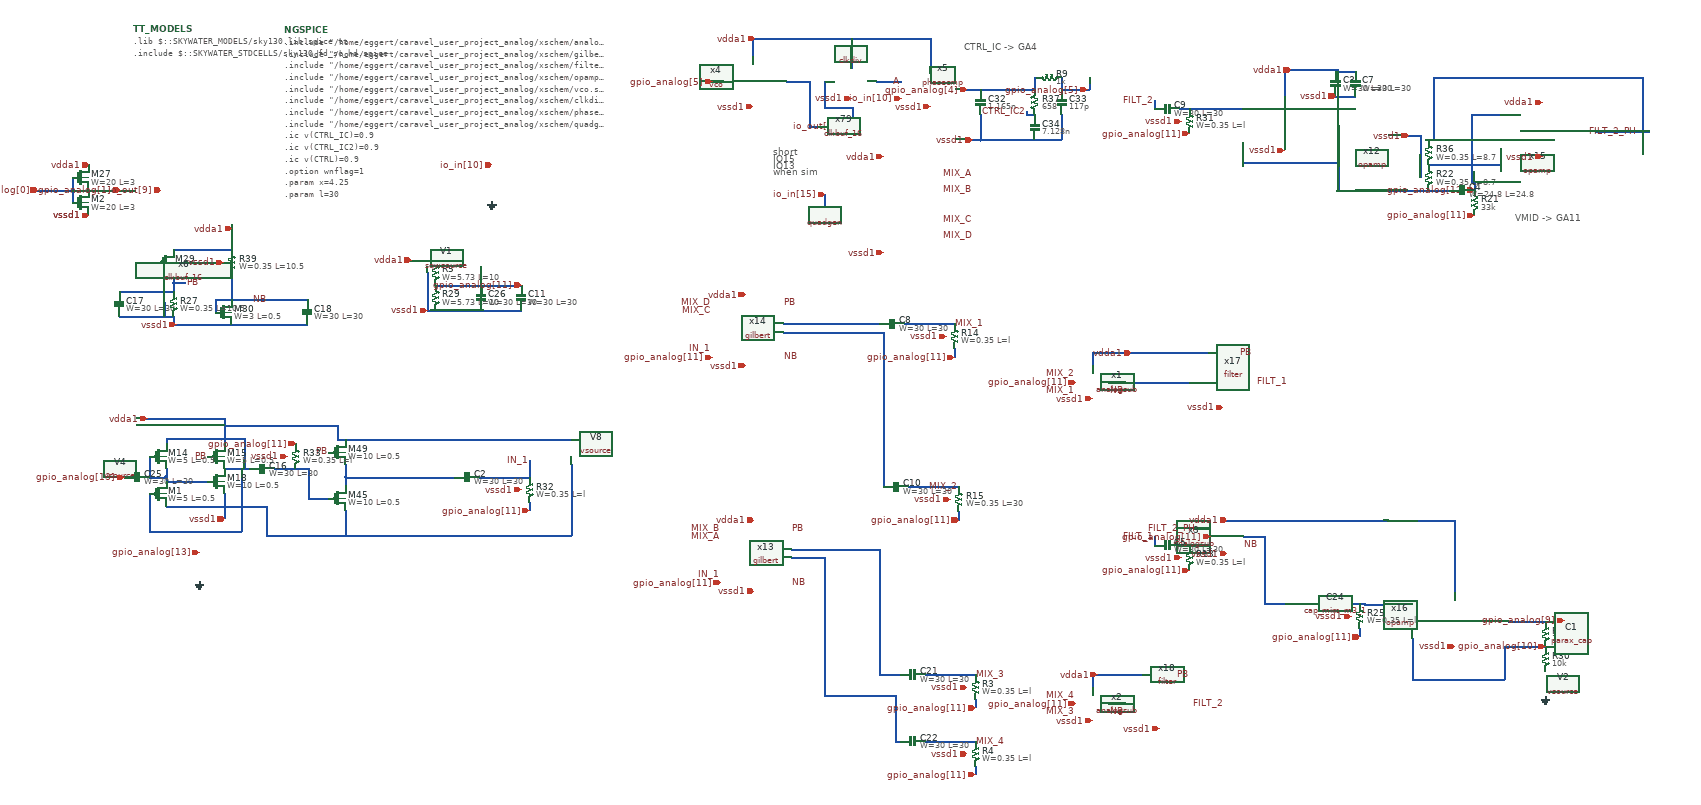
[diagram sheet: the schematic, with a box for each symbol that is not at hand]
v {xschem version=3.1.0 file_version=1.2 }
G {}
K {}
V {}
S {}
E {}
T {short 
IO15
IO13
when sim} 47.5 -2042.5 0 0 0.4 0.4 {}
T {VMID -> GA11} 1822.5 -1885 0 0 0.4 0.4 {}
T {CTRL_IC -> GA4} 505 -2295 0 0 0.4 0.4 {}
N -657.5 -1252.5 -537.5 -1252.5 {
lab=IN_1}
N -997.5 -1342.5 -437.5 -1342.5 {
lab=vdda1}
N 1395 -1940 1565 -1940 {
lab=#net1}
N 960 -2155 960 -2135 {
lab=FILT_2}
N 2135 -2080 2145 -2080 {
lab=FILT_2_PH}
N 1555 -1940 1665 -1940 {
lab=#net1}
N 1725 -1960 1725 -1940 {
lab=gpio_analog[12]}
N -437.5 -1282.5 -437.5 -1112.5 {
lab=vssd1}
N -1167.5 -1112.5 -977.5 -1112.5 {
lab=vssd1}
N -1067.5 -1202.5 -1017.5 -1202.5 {
lab=#net2}
N -977.5 -1252.5 -977.5 -1232.5 {
lab=#net3}
N -977.5 -1172.5 -977.5 -1112.5 {
lab=vssd1}
N -977.5 -1112.5 -437.5 -1112.5 {
lab=vssd1}
N -977.5 -1252.5 -717.5 -1252.5 {
lab=#net3}
N -762.5 -1712.5 -642.5 -1712.5 {
lab=gpio_analog[11]}
N 882.5 -1480 1042.5 -1480 {
lab=#net4}
N -1290 -1677.5 -1250 -1677.5 {
lab=NB}
N -1290 -1677.5 -1290 -1647.5 {
lab=NB}
N -1250 -1737.5 -1250 -1677.5 {
lab=NB}
N -1250 -1857.5 -1250 -1797.5 {
lab=vdda1}
N -1250 -1677.5 -1070 -1677.5 {
lab=NB}
N -1430 -1767.5 -1430 -1737.5 {
lab=PB}
N -1430 -1737.5 -1390 -1737.5 {
lab=PB}
N -1390 -1797.5 -1250 -1797.5 {
lab=vdda1}
N -1390 -1717.5 -1390 -1697.5 {
lab=PB}
N -1390 -1637.5 -1390 -1617.5 {
lab=vssd1}
N -1390 -1617.5 -1250 -1617.5 {
lab=vssd1}
N -1390 -1717.5 -1360 -1717.5 {
lab=PB}
N -1407.5 -1392.5 -1267.5 -1392.5 {
lab=vdda1}
N -1457.5 -1392.5 -1407.5 -1392.5 {
lab=vdda1}
N -1267.5 -1392.5 -1267.5 -1332.5 {
lab=vdda1}
N -1067.5 -1272.5 -1067.5 -1202.5 {
lab=#net2}
N -1267.5 -1272.5 -1207.5 -1272.5 {
lab=#net5}
N -1520 -1697.5 -1390 -1697.5 {
lab=PB}
N -1520 -1637.5 -1390 -1637.5 {
lab=vssd1}
N -1147.5 -1272.5 -1067.5 -1272.5 {
lab=#net2}
N -537.5 -1292.5 -537.5 -1252.5 {
lab=IN_1}
N -537.5 -1192.5 -537.5 -1172.5 {
lab=gpio_analog[11]}
N 370 -1230 490 -1230 {
lab=MIX_2}
N 490 -1170 490 -1150 {
lab=gpio_analog[11]}
N 310 -1310 310 -1230 {
lab=#net6}
N 410 -780 530 -780 {
lab=MIX_3}
N 530 -720 530 -700 {
lab=gpio_analog[11]}
N 410 -620 530 -620 {
lab=MIX_4}
N 530 -560 530 -540 {
lab=gpio_analog[11]}
N 340 -730 340 -620 {
lab=#net7}
N 340 -620 350 -620 {
lab=#net7}
N -1267.5 -1212.5 -1267.5 -1152.5 {
lab=vssd1}
N -1407.5 -1252.5 -1407.5 -1242.5 {
lab=#net8}
N -1407.5 -1242.5 -1307.5 -1242.5 {
lab=#net8}
N -1447.5 -1252.5 -1407.5 -1252.5 {
lab=#net8}
N -782.5 -1772.5 -762.5 -1772.5 {
lab=vdda1}
N 1595 -2070 1595 -1970 {
lab=vssd1}
N 1565 -2070 1595 -2070 {
lab=vssd1}
N 2015 -2080 2135 -2080 {
lab=FILT_2_PH}
N -977.5 -1282.5 -977.5 -1252.5 {
lab=#net3}
N -1390 -1737.5 -1390 -1717.5 {
lab=PB}
N -1407.5 -1272.5 -1407.5 -1252.5 {
lab=#net8}
N -822.5 -1772.5 -782.5 -1772.5 {
lab=vdda1}
N -107.5 -2200 -72.5 -2200 {
lab=gpio_analog[5]}
N -2.5 -2290 -2.5 -2260 {
lab=vdda1}
N 737.5 -2120 737.5 -2060 {
lab=vssd1}
N 542.5 -2060 737.5 -2060 {
lab=vssd1}
N 542.5 -2120 542.5 -2060 {
lab=vssd1}
N 502.5 -2180 587.5 -2180 {
lab=gpio_analog[4]}
N 647.5 -2180 672.5 -2180 {
lab=gpio_analog[4]}
N 517.5 -2060 542.5 -2060 {
lab=vssd1}
N 737.5 -2180 802.5 -2180 {
lab=gpio_analog[5]}
N 802.5 -2210 802.5 -2180 {
lab=gpio_analog[5]}
N 672.5 -2210 677.5 -2210 {
lab=gpio_analog[4]}
N 672.5 -2210 672.5 -2180 {
lab=gpio_analog[4]}
N 737.5 -2210 737.5 -2180 {
lab=gpio_analog[5]}
N 587.5 -2180 647.5 -2180 {
lab=gpio_analog[4]}
N 652.5 -2127.5 652.5 -2120 {
lab=CTRL_IC2}
N 652.5 -2120 672.5 -2120 {
lab=CTRL_IC2}
N 850 -1480 890 -1480 {
lab=#net4}
N 850 -710 890 -710 {
lab=#net9}
N 360 -1620 480 -1620 {
lab=MIX_1}
N 480 -1560 480 -1540 {
lab=gpio_analog[11]}
N 70 -1620 300 -1620 {
lab=#net10}
N 370 -1230 490 -1230 {
lab=MIX_2}
N 490 -1170 490 -1150 {
lab=gpio_analog[11]}
N 70 -1600 310 -1600 {
lab=#net6}
N 310 -1600 310 -1310 {
lab=#net6}
N 90 -1080 300 -1080 {
lab=#net11}
N 300 -1080 300 -780 {
lab=#net11}
N 90 -1060 170 -1060 {
lab=#net7}
N 170 -1060 170 -730 {
lab=#net7}
N 300 -780 350 -780 {
lab=#net11}
N 170 -730 340 -730 {
lab=#net7}
N 1717.5 -1960 1727.5 -1960 {
lab=gpio_analog[12]}
N 1807.5 -907.5 1897.5 -907.5 {
lab=gpio_analog[9]}
N 1797.5 -847.5 1897.5 -847.5 {
lab=gpio_analog[10]}
N 1797.5 -847.5 1797.5 -767.5 {
lab=gpio_analog[10]}
N 1577.5 -767.5 1797.5 -767.5 {
lab=gpio_analog[10]}
N 1577.5 -867.5 1577.5 -767.5 {
lab=gpio_analog[10]}
N 1450 -890 1450 -870 {
lab=gpio_analog[11]}
N 1052.5 -1130 1092.5 -1130 {
lab=FILT_2_PH}
N 1172.5 -1110 1222.5 -1110 {
lab=#net12}
N 1222.5 -1110 1222.5 -950 {
lab=#net12}
N 960 -1110 960 -1090 {
lab=FILT_1}
N 1022.5 -1090 1092.5 -1090 {
lab=#net13}
N 1012.5 -1090 1022.5 -1090 {
lab=#net13}
N 1222.5 -950 1272.5 -950 {
lab=#net12}
N 1322.5 -950 1332.5 -950 {
lab=#net14}
N 1322.5 -950 1462.5 -950 {
lab=#net14}
N 1787.5 -2040 1787.5 -2000 {
lab=#net15}
N 1617.5 -2000 1787.5 -2000 {
lab=#net15}
N 1717.5 -2120 1717.5 -1960 {
lab=gpio_analog[12]}
N 1717.5 -2120 1787.5 -2120 {
lab=gpio_analog[12]}
N 2127.5 -2210 2127.5 -2080 {
lab=FILT_2_PH}
N 1627.5 -2210 2127.5 -2210 {
lab=FILT_2_PH}
N 1627.5 -2210 1627.5 -2060 {
lab=FILT_2_PH}
N 1607.5 -2060 1627.5 -2060 {
lab=FILT_2_PH}
N 1462.5 -947.5 1577.5 -947.5 {
lab=#net14}
N 1462.5 -950 1462.5 -947.5 {
lab=#net14}
N -1220 -1345 -1220 -1272.5 {
lab=#net5}
N -1407.5 -1345 -1220 -1345 {
lab=#net5}
N -1407.5 -1345 -1407.5 -1332.5 {
lab=#net5}
N -1447.5 -1302.5 -1447.5 -1252.5 {
lab=#net8}
N -1447.5 -1212.5 -1447.5 -1122.5 {
lab=#net5}
N -1447.5 -1122.5 -1227.5 -1122.5 {
lab=#net5}
N -1227.5 -1272.5 -1227.5 -1122.5 {
lab=#net5}
N 1170 -2055 1170 -2015 {
lab=#net1}
N 1400 -2095 1400 -2005 {
lab=#net1}
N 1170 -2005 1400 -2005 {
lab=#net1}
N 1170 -2015 1170 -2005 {
lab=#net1}
N 1400 -2005 1400 -1945 {
lab=#net1}
N 1400 -1945 1400 -1940 {
lab=#net1}
N 1020 -2135 1170 -2135 {
lab=#net16}
N 1615 -2000 1617.5 -2000 {
lab=#net15}
N 232.5 -2260 232.5 -2230 {
lab=vdda1}
N 292.5 -2200 352.5 -2200 {
lab=A}
N 170 -1930 170 -1900 {
lab=io_in[15]}
N 1895 -907.5 1932.5 -907.5 {
lab=gpio_analog[9]}
N 1932.5 -910 1932.5 -907.5 {
lab=gpio_analog[9]}
N 1932.5 -910 1940 -910 {
lab=gpio_analog[9]}
N 152.5 -2092.5 155 -2092.5 {
lab=#net17}
N 132.5 -2092.5 152.5 -2092.5 {
lab=#net17}
N 132.5 -2200 132.5 -2092.5 {
lab=#net17}
N -1632.5 -1970 -1632.5 -1910 {
lab=gpio_analog[0]}
N -1592.5 -1940 -1500 -1940 {
lab=gpio_analog[1]}
N -1715 -1940 -1632.5 -1940 {
lab=gpio_analog[0]}
N 1392.5 -2225 1440 -2225 {
lab=vdda1}
N 1392.5 -2165 1440 -2165 {
lab=vssd1}
N -642.5 -1712.5 -557.5 -1712.5 {
lab=gpio_analog[11]}
N -652.5 -1655 -652.5 -1652.5 {
lab=vssd1}
N -652.5 -1652.5 -557.5 -1652.5 {
lab=vssd1}
N -782.5 -1742.5 -782.5 -1655 {
lab=vssd1}
N -782.5 -1652.5 -762.5 -1652.5 {
lab=vssd1}
N -782.5 -1655 -782.5 -1652.5 {
lab=vssd1}
N 77.5 -2200 132.5 -2200 {
lab=#net17}
N 235 -2137.5 235 -2092.5 {
lab=io_out[13]}
N 170 -2137.5 235 -2137.5 {
lab=io_out[13]}
N 170 -2200 170 -2137.5 {
lab=io_out[13]}
N 170 -2200 172.5 -2200 {
lab=io_out[13]}
N 810 -1550 1087.5 -1550 {
lab=vdda1}
N 810 -1550 810 -1520 {
lab=vdda1}
N 810 -780 930 -780 {
lab=vdda1}
N 810 -780 810 -750 {
lab=vdda1}
N 1132.5 -1150 1520 -1150 {
lab=vdda1}
N 1677.5 -1150 1677.5 -977.5 {
lab=vdda1}
N 1517.5 -1150 1677.5 -1150 {
lab=vdda1}
N 422.5 -2302.5 422.5 -2220 {
lab=vdda1}
N -2.5 -2302.5 422.5 -2302.5 {
lab=vdda1}
N -2.5 -2302.5 -2.5 -2290 {
lab=vdda1}
N 232.5 -2302.5 232.5 -2260 {
lab=vdda1}
N 1270 -2227.5 1270 -2165 {
lab=vdda1}
N 1270 -2227.5 1397.5 -2227.5 {
lab=vdda1}
N 1397.5 -2227.5 1397.5 -2225 {
lab=vdda1}
N -1250 -1617.5 -1070 -1617.5 {
lab=vssd1}
N -1410 -1670 -1410 -1637.5 {
lab=vssd1}
N -1407.5 -1182.5 -1267.5 -1182.5 {
lab=vssd1}
N -1267.5 -1182.5 -1167.5 -1182.5 {
lab=vssd1}
N -1167.5 -1182.5 -1167.5 -1112.5 {
lab=vssd1}
N -762.5 -1652.5 -647.5 -1652.5 {
lab=vssd1}
N -997.5 -1377.5 -997.5 -1342.5 {
lab=vdda1}
N -1267.5 -1377.5 -997.5 -1377.5 {
lab=vdda1}
C {devices/lab_pin.sym} -537.5 -1292.5 0 0 {name=l21 lab=IN_1
}
C {sky130_fd_pr/cap_mim_m3_1.sym} -687.5 -1252.5 1 0 {name=C2 model=cap_mim_m3_1 W=30 L=30 MF=10 spiceprefix=X}
C {devices/vsource.sym} -1327.5 -1032.5 0 0 {name=V4 value="SIN(0.9 1m 27000k)"}
C {devices/vsource.sym} -377.5 -1312.5 0 0 {name=V8 value=1.8}
C {devices/lab_pin.sym} 530 -780 2 0 {name=l34 lab=MIX_3}
C {devices/lab_pin.sym} 530 -620 2 0 {name=l35 lab=MIX_4}
C {devices/lab_wire.sym} 960 -2155 0 0 {name=l40 lab=FILT_2}
C {devices/lab_pin.sym} 450 -1980 2 0 {name=l5 lab=MIX_A}
C {devices/res.sym} 1725 -1910 2 1 {name=R21
value=33k
footprint=1206
device=resistor
m=1}
C {devices/lab_wire.sym} 2115 -2080 0 0 {name=l39 lab=FILT_2_PH}
C {sky130_fd_pr/cap_mim_m3_1.sym} 990 -2135 1 0 {name=C9 model=cap_mim_m3_1 W=30 L=30 MF=20 spiceprefix=X}
C {devices/gnd.sym} -1327.5 -1002.5 0 0 {name=l68 lab=GND}
C {sky130_fd_pr/pfet3_01v8_lvt.sym} -997.5 -1202.5 0 0 {name=M45
L=0.5
W=10
body=vdda1
nf=1 mult=1
model=pfet_01v8_lvt
spiceprefix=X
}
C {sky130_fd_pr/pfet3_01v8_lvt.sym} -997.5 -1312.5 0 0 {name=M49
L=0.5
W=10
body=vdda1
nf=1 mult=1
model=pfet_01v8_lvt
spiceprefix=X
}
C {sky130_fd_pr/nfet3_01v8_lvt.sym} -1270 -1647.5 0 0 {name=M30
L=0.5
W=3
body=vssd1
nf=1 mult=1
model=nfet_01v8_lvt
spiceprefix=X
}
C {devices/lab_pin.sym} -1200 -1677.5 2 0 {name=l29 lab=NB}
C {sky130_fd_pr/pfet3_01v8_lvt.sym} -1410 -1767.5 0 0 {name=M29
L=0.5
W=3
body=vdda1
nf=1 mult=1
model=pfet_01v8_lvt
spiceprefix=X
}
C {devices/lab_pin.sym} -1360 -1717.5 2 0 {name=l57 lab=PB}
C {devices/lab_pin.sym} -1017.5 -1312.5 0 0 {name=l78 lab=PB}
C {sky130_fd_pr/pfet3_01v8_lvt.sym} -1287.5 -1302.5 0 0 {name=M15
L=0.5
W=5
body=vdda1
nf=1 mult=1
model=pfet_01v8_lvt
spiceprefix=X
}
C {sky130_fd_pr/nfet3_01v8_lvt.sym} -1287.5 -1242.5 0 0 {name=M18
L=0.5
W=10
body=vssd1
nf=1 mult=1
model=nfet_01v8_lvt
spiceprefix=X
}
C {sky130_fd_pr/cap_mim_m3_1.sym} -1177.5 -1272.5 1 0 {name=C16 model=cap_mim_m3_1 W=30 L=30 MF=10 spiceprefix=X}
C {sky130_fd_pr/cap_mim_m3_1.sym} -1520 -1667.5 0 0 {name=C17 model=cap_mim_m3_1 W=30 L=30 MF=10 spiceprefix=X}
C {sky130_fd_pr/cap_mim_m3_1.sym} -1070 -1647.5 0 0 {name=C18 model=cap_mim_m3_1 W=30 L=30 MF=10 spiceprefix=X}
C {devices/res.sym} 1895 -877.5 0 0 {name=R28
value=10k
footprint=1206
device=resistor
m=1}
C {devices/res.sym} 1895 -817.5 0 0 {name=R30
value=10k
footprint=1206
device=resistor
m=1}
C {devices/lab_pin.sym} -1307.5 -1302.5 0 0 {name=l62 sig_type=std_logic lab=PB}
C {sky130_fd_pr/pfet3_01v8_lvt.sym} -1427.5 -1302.5 0 0 {name=M14
L=0.5
W=5
body=vdda1
nf=1 mult=1
model=pfet_01v8_lvt
spiceprefix=X
}
C {sky130_fd_pr/cap_mim_m3_1.sym} -1477.5 -1252.5 3 0 {name=C25 model=cap_mim_m3_1 W=30 L=30 MF=10 spiceprefix=X}
C {sky130_fd_pr/cap_mim_m3_1.sym} -652.5 -1682.5 2 0 {name=C26 model=cap_mim_m3_1 W=30 L=30 MF=10 spiceprefix=X}
C {devices/gnd.sym} 1895 -727.5 0 0 {name=l94 lab=GND}
C {devices/vsource.sym} 1937.5 -757.5 0 0 {name=V2 value=0.9
}
C {devices/capa.sym} 542.5 -2150 0 0 {name=C32
m=1
value=1.165n
footprint=1206
device="ceramic capacitor"}
C {devices/capa.sym} 737.5 -2150 0 0 {name=C33
m=1
value=117p
footprint=1206
device="ceramic capacitor"}
C {devices/res.sym} 707.5 -2210 1 0 {name=R9
value=1k
footprint=1206
device=resistor
m=1}
C {devices/res.sym} 672.5 -2150 2 0 {name=R37
value=658
footprint=1206
device=resistor
m=1}
C {devices/capa.sym} 672.5 -2090 0 0 {name=C34
m=1
value=7.128n
footprint=1206
device="ceramic capacitor"}
C {devices/lab_pin.sym} 652.5 -2127.5 2 1 {name=p32 lab=CTRL_IC2}
C {devices/lab_pin.sym} 352.5 -2200 2 1 {name=p6 lab=A
}
C {devices/lab_pin.sym} 450 -1940 2 0 {name=l133 lab=MIX_B
}
C {devices/lab_pin.sym} 450 -1870 2 0 {name=l134 lab=MIX_C}
C {devices/lab_pin.sym} 450 -1830 2 0 {name=l135 lab=MIX_D
}
C {sky130_fd_pr/cap_mim_m3_1.sym} 380 -780 1 0 {name=C21 model=cap_mim_m3_1 W=30 L=30 MF=10 spiceprefix=X}
C {sky130_fd_pr/cap_mim_m3_1.sym} 380 -620 1 0 {name=C22 model=cap_mim_m3_1 W=30 L=30 MF=10 spiceprefix=X}
C {sky130_fd_pr/res_xhigh_po_0p35.sym} -1250 -1767.5 0 0 {name=R39
W=0.35
L=10.5
model=res_xhigh_po_0p35
spiceprefix=X
 mult=1}
C {sky130_fd_pr/res_xhigh_po_0p35.sym} -1390 -1667.5 0 0 {name=R27
W=0.35
L=10.5
model=res_xhigh_po_0p35
spiceprefix=X
 mult=1}
C {sky130_fd_pr/res_xhigh_po_5p73.sym} -762.5 -1742.5 0 0 {name=R5
W=5.73
L=10
model=res_xhigh_po_5p73
spiceprefix=X
 mult=1}
C {sky130_fd_pr/res_xhigh_po_5p73.sym} -762.5 -1682.5 0 0 {name=R29
W=5.73
L=10
model=res_xhigh_po_5p73
spiceprefix=X
 mult=1}
C {sky130_fd_pr/res_xhigh_po_0p35.sym} -1097.5 -1302.5 0 0 {name=R33
W=0.35
L=l
model=res_xhigh_po_0p35
spiceprefix=X
 mult=1}
C {sky130_fd_pr/res_xhigh_po_0p35.sym} -537.5 -1222.5 0 0 {name=R32
W=0.35
L=l
model=res_xhigh_po_0p35
spiceprefix=X
 mult=1}
C {sky130_fd_pr/res_xhigh_po_0p35.sym} 530 -750 0 0 {name=R3
W=0.35
L=l
model=res_xhigh_po_0p35
spiceprefix=X
 mult=1}
C {sky130_fd_pr/res_xhigh_po_0p35.sym} 530 -590 0 0 {name=R4
W=0.35
L=l
model=res_xhigh_po_0p35
spiceprefix=X
 mult=1}
C {sky130_fd_pr/res_xhigh_po_0p35.sym} 1042.5 -2105 0 0 {name=R31
W=0.35
L=l
model=res_xhigh_po_0p35
spiceprefix=X
 mult=1}
C {sky130_fd_pr/res_xhigh_po_0p35.sym} 1615 -2030 0 0 {name=R36
W=0.35
L=8.7
model=res_xhigh_po_0p35
spiceprefix=X
 mult=1}
C {sky130_fd_pr/res_xhigh_po_0p35.sym} 1615 -1970 0 0 {name=R22
W=0.35
L=8.7
model=res_xhigh_po_0p35
spiceprefix=X
 mult=1}
C {xschemwrap/analogsub.sym} 810 -1480 0 0 {name=x1}
C {devices/lab_pin.sym} 850 -1460 2 0 {name=l60 lab=NB}
C {devices/lab_pin.sym} 770 -1460 0 0 {name=l85 lab=MIX_1}
C {devices/lab_pin.sym} 770 -1500 0 0 {name=l86 lab=MIX_2}
C {xschemwrap/analogsub.sym} 810 -710 0 0 {name=x2}
C {devices/lab_pin.sym} 850 -690 2 0 {name=l8 lab=NB}
C {devices/lab_pin.sym} 770 -690 0 0 {name=l47 lab=MIX_3}
C {devices/lab_pin.sym} 770 -730 0 0 {name=l48 lab=MIX_4}
C {sky130_fd_pr/cap_mim_m3_1.sym} 330 -1620 1 0 {name=C8 model=cap_mim_m3_1 W=30 L=30 MF=10 spiceprefix=X}
C {devices/lab_pin.sym} 480 -1620 2 0 {name=l115 lab=MIX_1}
C {sky130_fd_pr/res_xhigh_po_0p35.sym} 480 -1590 0 0 {name=R14
W=0.35
L=l
model=res_xhigh_po_0p35
spiceprefix=X
 mult=1}
C {devices/lab_pin.sym} 490 -1230 1 0 {name=l139 lab=MIX_2}
C {sky130_fd_pr/cap_mim_m3_1.sym} 340 -1230 1 0 {name=C10 model=cap_mim_m3_1 W=30 L=30 MF=10 spiceprefix=X}
C {sky130_fd_pr/res_xhigh_po_0p35.sym} 490 -1200 0 0 {name=R15
W=0.35
L=30
model=res_xhigh_po_0p35
spiceprefix=X
 mult=1}
C {xschemwrap/gilbert.sym} 0 -1070 0 0 {name=x13}
C {devices/lab_pin.sym} -80 -1020 0 0 {name=l58 lab=IN_1
}
C {devices/lab_pin.sym} 90 -1130 2 0 {name=l67 lab=PB}
C {devices/lab_pin.sym} 90 -1000 2 0 {name=l82 lab=NB}
C {xschemwrap/gilbert.sym} -20 -1610 0 0 {name=x14}
C {devices/lab_pin.sym} -100 -1670 0 0 {name=l100 lab=MIX_D
}
C {devices/lab_pin.sym} -100 -1650 0 0 {name=l137 lab=MIX_C}
C {devices/lab_pin.sym} -100 -1560 0 0 {name=l142 lab=IN_1
}
C {devices/lab_pin.sym} 70 -1540 2 0 {name=l144 lab=NB}
C {devices/lab_pin.sym} -80 -1130 0 0 {name=l18 lab=MIX_B
}
C {devices/lab_pin.sym} -80 -1110 0 0 {name=l19 lab=MIX_A}
C {xschemwrap/opamp.sym} 1887.5 -2080 0 0 {name=x15}
C {xschemwrap/opamp.sym} 1677.5 -907.5 0 0 {name=x16}
C {sky130_fd_pr/cap_mim_m3_1.sym} 1300 -950 1 0 {name=C24 model=cap_mim_m3_1 W=30 L=30 MF=20 spiceprefix=X}
C {sky130_fd_pr/res_xhigh_po_0p35.sym} 1450 -920 0 0 {name=R25
W=0.35
L=l
model=res_xhigh_po_0p35
spiceprefix=X
 mult=1}
C {xschemwrap/analogsub.sym} 1132.5 -1110 0 0 {name=x3}
C {devices/lab_wire.sym} 1060 -1130 0 0 {name=l9 lab=FILT_2_PH}
C {devices/lab_pin.sym} 1172.5 -1090 2 0 {name=l61 lab=NB}
C {sky130_fd_pr/cap_mim_m3_1.sym} 990 -1090 1 0 {name=C5 model=cap_mim_m3_1 W=30 L=30 MF=20 spiceprefix=X}
C {sky130_fd_pr/res_xhigh_po_0p35.sym} 1042.5 -1060 0 0 {name=R13
W=0.35
L=l
model=res_xhigh_po_0p35
spiceprefix=X
 mult=1}
C {devices/lab_wire.sym} 960 -1110 0 0 {name=l73 lab=FILT_1}
C {xschemwrap/vco.sym} -2.5 -2200 0 0 {name=x4}
C {sky130_fd_pr/pfet3_01v8_lvt.sym} -1427.5 -1212.5 0 0 {name=M1
L=0.5
W=5
body=vdda1
nf=1 mult=1
model=pfet_01v8_lvt
spiceprefix=X
}
C {devices/code_shown.sym} -1125 -2322.5 0 0 {name=NGSPICE
only_toplevel=true
value="
.include \\"/home/eggert/caravel_user_project_analog/xschem/analogsub.spice\\"
.include \\"/home/eggert/caravel_user_project_analog/xschem/gilbert.spice\\"
.include \\"/home/eggert/caravel_user_project_analog/xschem/filter.spice\\"
.include \\"/home/eggert/caravel_user_project_analog/xschem/opamp.spice\\"
.include \\"/home/eggert/caravel_user_project_analog/xschem/vco.spice\\"
.include \\"/home/eggert/caravel_user_project_analog/xschem/clkdiv.spice\\"
.include \\"/home/eggert/caravel_user_project_analog/xschem/phasecmp.spice\\"
.include \\"/home/eggert/caravel_user_project_analog/xschem/quadgen.spice\\"

.ic v(CTRL_IC)=0.9
.ic v(CTRL_IC2)=0.9
.ic v(CTRL)=0.9

.option wnflag=1
.param x=4.25
.param l=30
vvcc vcc 0 dc 1.8
vvss vss 0 0
.control
tran 30p 15u 13u
write sim.raw
.endc
" 
}
C {devices/code.sym} -1485 -2325 0 0 {name=TT_MODELS
only_toplevel=true
format="tcleval( @value )"
value=".lib $::SKYWATER_MODELS/sky130.lib.spice tt
.include $::SKYWATER_STDCELLS/sky130_fd_sc_hd.spice
"
spice_ignore=false}
C {xschemwrap/opamp.sym} 1270 -2095 0 0 {name=x12}
C {xschemwrap/filter.sym} 1122.5 -1480 0 0 {name=x17}
C {devices/lab_wire.sym} 1202.5 -1480 2 0 {name=l43 lab=FILT_1}
C {devices/lab_pin.sym} 1162.5 -1550 2 0 {name=l51 lab=PB}
C {devices/lab_pin.sym} 70 -1670 2 0 {name=l25 lab=PB}
C {xschemwrap/filter.sym} 970 -710 0 0 {name=x18}
C {devices/lab_wire.sym} 1050 -710 2 0 {name=l33 lab=FILT_2}
C {devices/lab_pin.sym} 1010 -780 2 0 {name=l64 lab=PB}
C {xschemwrap/clkdiv.sym} 232.5 -2200 0 0 {}
C {xschemwrap/phasecmp.sym} 422.5 -2180 0 0 {name=x5}
C {devices/sqwsource.sym} -627.5 -1942.5 0 0 {name=V1 vhi=1.8 freq=4e6}
C {devices/gnd.sym} -627.5 -1912.5 0 1 {name=l74 lab=GND}
C {xschemwrap/quadgen.sym} 310 -1900 0 0 {}
C {devices/parax_cap.sym} 1940 -900 0 0 {name=C1 gnd=0 value=10p m=1}
C {devices/ipin.sym} 1725 -1940 2 0 {name=p8 lab=gpio_analog[12]}
C {sky130_fd_pr/cap_mim_m3_1.sym} 1392.5 -2195 2 0 {name=C3 model=cap_mim_m3_1 W=30 L=30 MF=10 spiceprefix=X}
C {devices/ipin.sym} 1940 -910 2 0 {name=p10 lab=gpio_analog[9]}
C {devices/ipin.sym} 1895 -847.5 2 0 {name=p11 lab=gpio_analog[10]}
C {devices/ipin.sym} 170 -1930 0 0 {name=p12 lab=io_in[15]}
C {devices/ipin.sym} 235 -2092.5 2 0 {name=p13 lab=io_out[13]}
C {sky130_stdcells/clkbuf_16.sym} 195 -2092.5 0 0 {name=x79 VGND=vssd1 VNB=vssd1 VPB=vdda1 VPWR=vdda1 prefix=sky130_fd_sc_hd__ 
}
C {devices/ipin.sym} -100 -2200 3 0 {name=p14 lab=gpio_analog[5]}
C {sky130_fd_pr/nfet3_01v8.sym} -1612.5 -1910 0 0 {name=M2
L=3
W=20
body=vssd1
nf=1 mult=1
model=nfet_01v8
spiceprefix=X
}
C {sky130_fd_pr/pfet3_01v8.sym} -1612.5 -1970 0 0 {name=M27
L=3
W=20
body=vdda1
nf=1 mult=1
model=pfet_01v8
spiceprefix=X
}
C {sky130_stdcells/clkbuf_16.sym} -1460 -1940 0 0 {name=x6 VGND=vssd1 VNB=vssd1 VPB=vdda1 VPWR=vdda1 prefix=sky130_fd_sc_hd__ 
}
C {devices/ipin.sym} -1715 -1940 0 0 {name=p17 lab=gpio_analog[0]}
C {devices/ipin.sym} -1517.5 -1940 1 0 {name=p18 lab=gpio_analog[1]}
C {devices/ipin.sym} -1420 -1940 1 0 {name=p19 lab=io_out[9]}
C {sky130_fd_pr/cap_mim_m3_1.sym} 1695 -1940 1 0 {name=C4 model=cap_mim_m3_1 W=24.8 L=24.8 MF=4 spiceprefix=X}
C {sky130_fd_pr/cap_mim_m3_1.sym} 1440 -2195 0 0 {name=C7 model=cap_mim_m3_1 W=30 L=30 MF=10 spiceprefix=X}
C {sky130_fd_pr/cap_mim_m3_1.sym} -557.5 -1682.5 0 0 {name=C11 model=cap_mim_m3_1 W=30 L=30 MF=10 spiceprefix=X}
C {devices/ipin.sym} -1507.5 -1252.5 0 0 {name=p23 lab="gpio_analog[13]"}
C {devices/ipin.sym} 352.5 -2160 0 0 {name=p3 lab=io_in[10]}
C {devices/ipin.sym} 797.5 -2180 3 0 {name=p5 lab=gpio_analog[5]}
C {devices/ipin.sym} -1327.5 -1072.5 0 0 {name=p1 lab="gpio_analog[13]"}
C {devices/ipin.sym} 510 -2180 1 0 {name=p2 lab=gpio_analog[4]}
C {devices/ipin.sym} -1592.5 -1880 0 0 {name=p4 lab=vssd1}
C {devices/ipin.sym} -1382.5 -1617.5 0 0 {name=p7 lab=vssd1}
C {devices/ipin.sym} -1592.5 -1880 0 0 {name=p9 lab=vssd1}
C {devices/ipin.sym} -1270 -1767.5 0 0 {name=p15 lab=vssd1}
C {devices/ipin.sym} -1117.5 -1302.5 0 0 {name=p20 lab=vssd1}
C {devices/ipin.sym} -557.5 -1222.5 0 0 {name=p21 lab=vssd1}
C {devices/ipin.sym} -1267.5 -1152.5 0 0 {name=p22 lab=vssd1}
C {devices/ipin.sym} -782.5 -1652.5 0 0 {name=p24 lab=vssd1}
C {devices/ipin.sym} 510 -750 0 0 {name=p25 lab=vssd1}
C {devices/ipin.sym} 510 -590 0 0 {name=p26 lab=vssd1}
C {devices/ipin.sym} 0 -980 0 0 {name=p27 lab=vssd1}
C {devices/ipin.sym} 470 -1200 0 0 {name=p28 lab=vssd1}
C {devices/ipin.sym} 460 -1590 0 0 {name=p29 lab=vssd1}
C {devices/ipin.sym} -20 -1520 0 0 {name=p30 lab=vssd1}
C {devices/ipin.sym} 310 -1790 0 0 {name=p31 lab=vssd1}
C {devices/ipin.sym} -2.5 -2140 0 0 {name=p33 lab=vssd1}
C {devices/ipin.sym} 232.5 -2160 0 0 {name=p34 lab=vssd1}
C {devices/ipin.sym} 422.5 -2140 0 0 {name=p35 lab=vssd1}
C {devices/ipin.sym} 522.5 -2060 0 0 {name=p36 lab=vssd1}
C {devices/ipin.sym} 1022.5 -2105 0 0 {name=p37 lab=vssd1}
C {devices/ipin.sym} 1270 -2035 0 0 {name=p38 lab=vssd1}
C {devices/ipin.sym} 1392.5 -2165 0 0 {name=p39 lab=vssd1}
C {devices/ipin.sym} 1122.5 -1420 0 0 {name=p40 lab=vssd1}
C {devices/ipin.sym} 1887.5 -2020 0 0 {name=p41 lab=vssd1}
C {devices/ipin.sym} 1567.5 -2070 0 0 {name=p42 lab=vssd1}
C {devices/ipin.sym} 810 -1440 0 0 {name=p43 lab=vssd1}
C {devices/ipin.sym} 1022.5 -1060 0 0 {name=p44 lab=vssd1}
C {devices/ipin.sym} 1132.5 -1070 0 0 {name=p45 lab=vssd1}
C {devices/ipin.sym} 1430 -920 0 0 {name=p46 lab=vssd1}
C {devices/ipin.sym} 1677.5 -847.5 0 0 {name=p47 lab=vssd1}
C {devices/ipin.sym} 810 -670 0 0 {name=p48 lab=vssd1}
C {devices/ipin.sym} 970 -650 0 0 {name=p49 lab=vssd1}
C {devices/ipin.sym} -1592.5 -2000 0 0 {name=p50 lab=vdda1}
C {devices/ipin.sym} -1250 -1847.5 0 0 {name=p51 lab=vdda1}
C {devices/ipin.sym} -820 -1772.5 0 0 {name=p52 lab=vdda1}
C {devices/ipin.sym} -1452.5 -1392.5 0 0 {name=p53 lab=vdda1}
C {devices/ipin.sym} 2.5 -2302.5 0 0 {name=p54 lab=vdda1}
C {devices/ipin.sym} 310 -2020 0 0 {name=p55 lab=vdda1}
C {devices/ipin.sym} -20 -1690 0 0 {name=p56 lab=vdda1}
C {devices/ipin.sym} 0 -1150 0 0 {name=p57 lab=vdda1}
C {devices/ipin.sym} 822.5 -780 0 0 {name=p58 lab=vdda1}
C {devices/ipin.sym} 1132.5 -1150 0 0 {name=p59 lab=vdda1}
C {devices/ipin.sym} 902.5 -1550 0 0 {name=p60 lab=vdda1}
C {devices/ipin.sym} 1285 -2227.5 0 0 {name=p61 lab=vdda1}
C {devices/ipin.sym} 1887.5 -2150 0 0 {name=p62 lab=vdda1}
C {devices/ipin.sym} 1725 -1880 2 0 {name=p63 lab=gpio_analog[11]}
C {devices/ipin.sym} 1042.5 -2075 2 0 {name=p64 lab=gpio_analog[11]}
C {devices/ipin.sym} 770 -1480 0 0 {name=p65 lab=gpio_analog[11]}
C {devices/ipin.sym} 1092.5 -1110 0 0 {name=p66 lab=gpio_analog[11]}
C {devices/ipin.sym} 1042.5 -1030 2 0 {name=p67 lab=gpio_analog[11]}
C {devices/ipin.sym} 1450 -870 2 0 {name=p68 lab=gpio_analog[11]}
C {devices/ipin.sym} 770 -710 0 0 {name=p69 lab=gpio_analog[11]}
C {devices/ipin.sym} 530 -700 0 0 {name=p70 lab=gpio_analog[11]}
C {devices/ipin.sym} 530 -540 2 0 {name=p71 lab=gpio_analog[11]}
C {devices/ipin.sym} 490 -1150 2 0 {name=p72 lab=gpio_analog[11]}
C {devices/ipin.sym} 480 -1540 2 0 {name=p73 lab=gpio_analog[11]}
C {devices/ipin.sym} -80 -1000 0 0 {name=p74 lab=gpio_analog[11]}
C {devices/ipin.sym} -100 -1540 0 0 {name=p75 lab=gpio_analog[11]}
C {devices/ipin.sym} -557.5 -1712.5 2 0 {name=p76 lab=gpio_analog[11]}
C {devices/ipin.sym} -1097.5 -1332.5 1 0 {name=p77 lab=gpio_analog[11]}
C {devices/ipin.sym} -537.5 -1172.5 2 0 {name=p78 lab=gpio_analog[11]}
C {devices/ipin.sym} -627.5 -2000 0 0 {name=p16 lab=io_in[10]}
